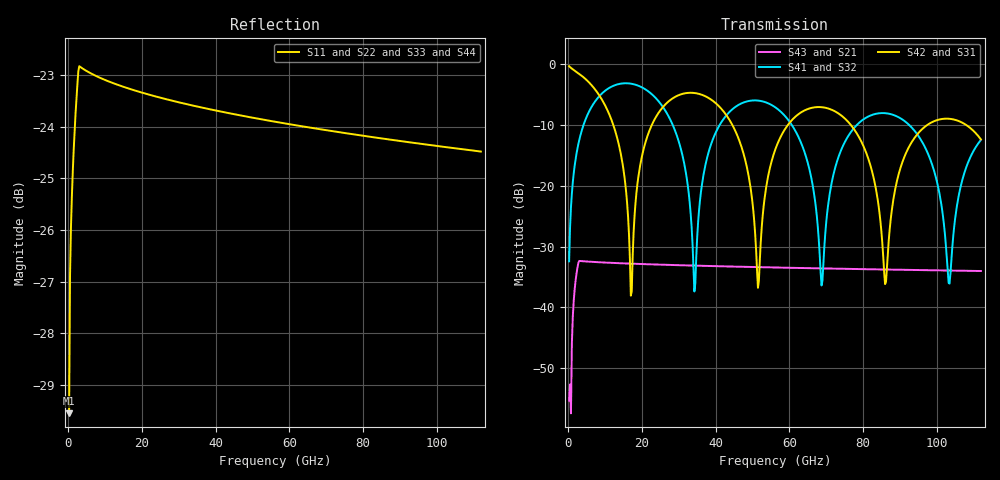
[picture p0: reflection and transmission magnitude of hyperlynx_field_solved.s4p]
! 3DIC-X TEST FIXTURE -- emulates the FORMAT of a vendor export. Not vendor data, not measured, not field-solved.
! HyperLynx field-solved export (FIXTURE) -- ports 1,2 = TX P/N; 3,4 = RX P/N
# GHz S RI R 50
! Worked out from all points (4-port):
!   448 points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, 250 MHz to 112 GHz, reference 50 ohm
!   strongest paths, dB at 250 MHz, 28.25 GHz, 56.25 GHz, 84.25 GHz, 112 GHz:
!     S42: -0.4, -5.7, -14.0, -23.4, -12.4
!     S31: -0.4, -5.7, -14.0, -23.4, -12.4
!     S41: -32.4, -9.9, -7.2, -8.1, -12.5
!     S32: -32.4, -9.9, -7.2, -8.1, -12.5
!     S43: -55.3, -33.0, -33.4, -33.8, -34.0
!     S21: -55.3, -33.0, -33.4, -33.8, -34.0
!   lowest |S11| = -29.6 dB at 250 MHz (marker M1), VSWR 1.07, Z = 53.4 + j0 ohm
!   |S11| at or under -10 dB: start of sweep to end of sweep
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0.25  0.0333 0  -0.00172 0  -0.6342 -0.715  0.0167 -0.0171
      -0.00172 0  0.0333 0  0.0167 -0.0171  -0.6342 -0.715
      -0.6342 -0.715  0.0167 -0.0171  0.0333 0  -0.00172 0
      0.0167 -0.0171  -0.6342 -0.715  -0.00172 0  0.0333 0
17  0.0686 0  0.0229 0  -0.00277 -0.0122  0.2481 -0.6405
    0.0229 0  0.0686 0  0.2481 -0.6405  -0.00277 -0.0122
    -0.00277 -0.0122  0.2481 -0.6405  0.0686 0  0.0229 0
    0.2481 -0.6405  -0.00277 -0.0122  0.0229 0  0.0686 0
34.25  0.0661 0  0.022 0  -0.1332 0.56  0.000907 0.0135
       0.022 0  0.0661 0  0.000907 0.0135  -0.1332 0.56
       -0.1332 0.56  0.000907 0.0135  0.0661 0  0.022 0
       0.000907 0.0135  -0.1332 0.56  0.022 0  0.0661 0
51.5  0.0643 0  0.0214 0  -0.000961 -0.0145  0.069 -0.4942
      0.0214 0  0.0643 0  0.069 -0.4942  -0.000961 -0.0145
      -0.000961 -0.0145  0.069 -0.4942  0.0643 0  0.0214 0
      0.069 -0.4942  -0.000961 -0.0145  0.0214 0  0.0643 0
68.75  0.0627 0  0.0209 0  -0.0318 0.4392  0.00172 0.015
       0.0209 0  0.0627 0  0.00172 0.015  -0.0318 0.4392
       -0.0318 0.4392  0.00172 0.015  0.0627 0  0.0209 0
       0.00172 0.015  -0.0318 0.4392  0.0209 0  0.0627 0
86  0.0614 0  0.0205 0  -0.00275 -0.0153  0.0132 -0.3929
    0.0205 0  0.0614 0  0.0132 -0.3929  -0.00275 -0.0153
    -0.00275 -0.0153  0.0132 -0.3929  0.0614 0  0.0205 0
    0.0132 -0.3929  -0.00275 -0.0153  0.0205 0  0.0614 0
112  0.0597 0  0.0199 0  -0.0515 -0.2339  0.2258 -0.0717
     0.0199 0  0.0597 0  0.2258 -0.0717  -0.0515 -0.2339
     -0.0515 -0.2339  0.2258 -0.0717  0.0597 0  0.0199 0
     0.2258 -0.0717  -0.0515 -0.2339  0.0199 0  0.0597 0
